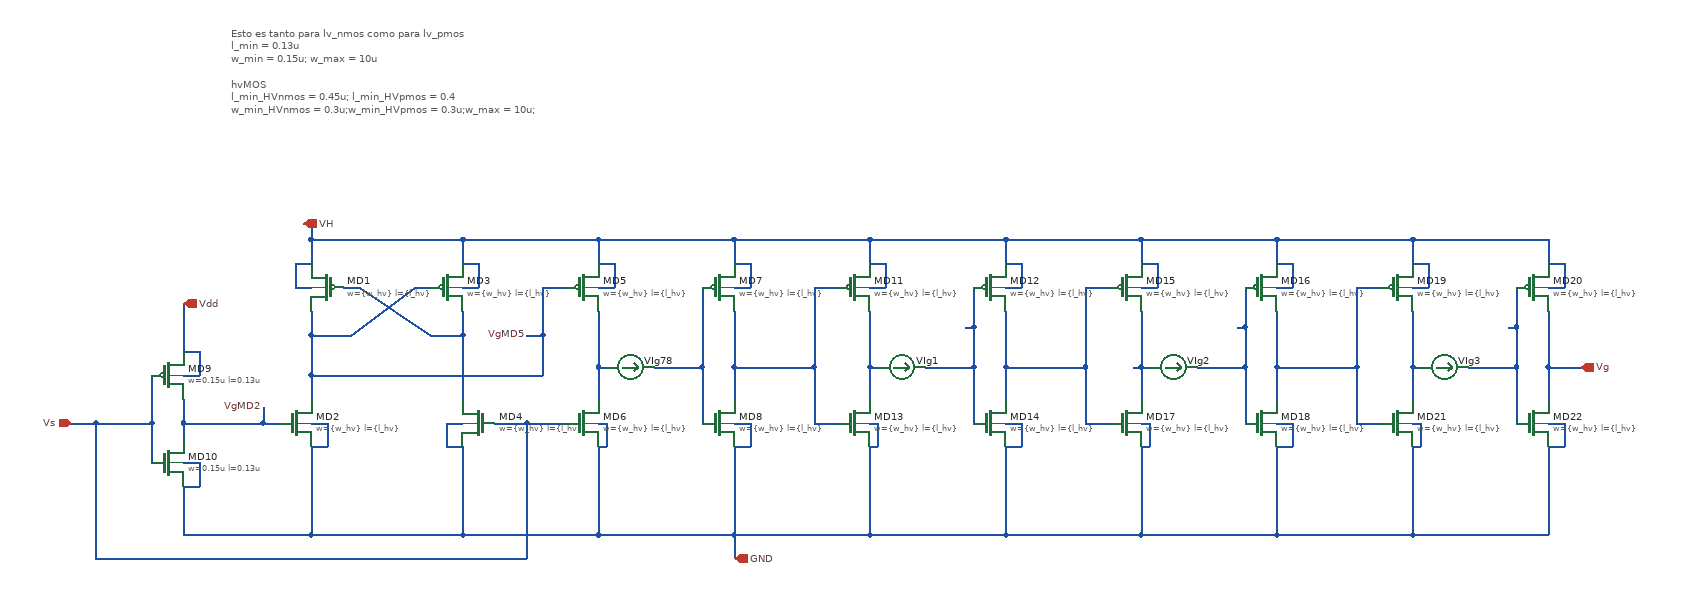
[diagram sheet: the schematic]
v {xschem version=3.4.5 file_version=1.2
}
G {}
K {}
V {}
S {}
E {}
T {Esto es tanto para lv_nmos como para lv_pmos
l_min = 0.13u
w_min = 0.15u; w_max = 10u

hvMOS
l_min_HVnmos = 0.45u; l_min_HVpmos = 0.4
w_min_HVnmos = 0.3u;w_min_HVpmos = 0.3u;w_max = 10u;
} -30 -500 0 0 0.4 0.4 {}
N -90 80 -90 140 {
lab=GND}
N -90 -0 -90 20 {
lab=VgMD2}
N -90 -30 -90 -0 {
lab=VgMD2}
N 70 -60 70 -30 {
lab=VgMD5}
N 10 0 30 0 {
lab=VgMD2}
N 110 -170 130 -170 {
lab=#net1}
N 430 -70 430 -30 {
lab=#net2}
N 260 -110 260 -30 {
lab=#net1}
N 130 -170 220 -110 {
lab=#net1}
N 220 -110 260 -110 {
lab=#net1}
N 260 -140 260 -110 {
lab=#net1}
N 70 -110 120 -110 {
lab=VgMD5}
N 70 -140 70 -110 {
lab=VgMD5}
N 200 -170 220 -170 {
lab=VgMD5}
N 120 -110 200 -170 {
lab=VgMD5}
N 70 -60 360 -60 {
lab=VgMD5}
N 70 -110 70 -60 {
lab=VgMD5}
N 360 -110 360 -60 {
lab=VgMD5}
N 360 -170 390 -170 {
lab=VgMD5}
N 340 0 390 0 {
lab=Vs}
N 340 0 340 170 {
lab=Vs}
N 300 0 340 0 {
lab=Vs}
N -200 170 340 170 {
lab=Vs}
N -200 -0 -200 170 {
lab=Vs}
N 430 140 600 140 {
lab=GND}
N 600 30 600 140 {
lab=GND}
N 430 30 430 140 {
lab=GND}
N 260 140 430 140 {
lab=GND}
N 260 30 260 140 {
lab=GND}
N 70 140 260 140 {
lab=GND}
N 70 30 70 140 {
lab=GND}
N -90 140 70 140 {
lab=GND}
N -130 0 -130 50 {
lab=Vs}
N -200 0 -130 0 {
lab=Vs}
N -130 -60 -130 0 {
lab=Vs}
N 560 -70 560 0 {
lab=#net3}
N 430 -140 430 -70 {
lab=#net2}
N 600 -70 600 -30 {
lab=#net4}
N 70 -230 70 -200 {
lab=VH}
N 430 -230 600 -230 {
lab=VH}
N 600 -230 600 -200 {
lab=VH}
N 430 -230 430 -200 {
lab=VH}
N 260 -230 430 -230 {
lab=VH}
N 260 -230 260 -200 {
lab=VH}
N 70 -230 260 -230 {
lab=VH}
N 70 -250 70 -230 {
lab=VH}
N 60 -250 70 -250 {
lab=VH}
N -90 -150 -90 -90 {
lab=Vdd}
N -230 0 -200 -0 {
lab=Vs}
N 600 140 600 170 {
lab=GND}
N 600 -70 700 -70 {
lab=#net4}
N 600 -140 600 -70 {
lab=#net4}
N 70 0 90 0 {
lab=GND}
N 90 0 90 30 {
lab=GND}
N 70 30 90 30 {
lab=GND}
N 240 0 260 0 {
lab=GND}
N 240 0 240 30 {
lab=GND}
N 240 30 260 30 {
lab=GND}
N 430 0 440 0 {
lab=GND}
N 440 0 440 30 {
lab=GND}
N 430 30 440 30 {
lab=GND}
N 600 0 620 0 {
lab=GND}
N 620 0 620 30 {
lab=GND}
N 600 30 620 30 {
lab=GND}
N 50 -170 70 -170 {
lab=VH}
N 50 -200 50 -170 {
lab=VH}
N 50 -200 70 -200 {
lab=VH}
N 260 -170 280 -170 {
lab=VH}
N 280 -200 280 -170 {
lab=VH}
N 260 -200 280 -200 {
lab=VH}
N 430 -170 450 -170 {
lab=VH}
N 450 -200 450 -170 {
lab=VH}
N 430 -200 450 -200 {
lab=VH}
N 600 -170 620 -170 {
lab=VH}
N 620 -200 620 -170 {
lab=VH}
N 600 -200 620 -200 {
lab=VH}
N -90 -60 -70 -60 {
lab=Vdd}
N -70 -90 -70 -60 {
lab=Vdd}
N -90 -90 -70 -90 {
lab=Vdd}
N -90 50 -70 50 {
lab=GND}
N -70 50 -70 80 {
lab=GND}
N -90 80 -70 80 {
lab=GND}
N 10 -20 10 0 {
lab=VgMD2}
N -90 0 10 0 {
lab=VgMD2}
N 340 -110 360 -110 {
lab=VgMD5}
N 360 -170 360 -110 {
lab=VgMD5}
N 500 -70 560 -70 {
lab=#net3}
N 430 -70 440 -70 {
lab=#net2}
N 560 -170 560 -70 {
lab=#net3}
N 770 -70 770 -30 {
lab=#net5}
N 700 -170 730 -170 {
lab=#net4}
N 700 -0 730 0 {
lab=#net4}
N 770 140 940 140 {
lab=GND}
N 940 30 940 140 {
lab=GND}
N 770 30 770 140 {
lab=GND}
N 600 140 770 140 {
lab=GND}
N 900 -70 900 0 {
lab=#net6}
N 770 -140 770 -70 {
lab=#net5}
N 900 -120 900 -70 {
lab=#net6}
N 940 -70 940 -30 {
lab=#net7}
N 770 -230 940 -230 {
lab=VH}
N 940 -230 940 -200 {
lab=VH}
N 770 -230 770 -200 {
lab=VH}
N 600 -230 770 -230 {
lab=VH}
N 940 -70 1040 -70 {
lab=#net7}
N 940 -140 940 -70 {
lab=#net7}
N 770 0 780 0 {
lab=GND}
N 780 0 780 30 {
lab=GND}
N 770 30 780 30 {
lab=GND}
N 940 0 960 0 {
lab=GND}
N 960 0 960 30 {
lab=GND}
N 940 30 960 30 {
lab=GND}
N 770 -170 790 -170 {
lab=VH}
N 790 -200 790 -170 {
lab=VH}
N 770 -200 790 -200 {
lab=VH}
N 940 -170 960 -170 {
lab=VH}
N 960 -200 960 -170 {
lab=VH}
N 940 -200 960 -200 {
lab=VH}
N 840 -70 900 -70 {
lab=#net6}
N 770 -70 780 -70 {
lab=#net5}
N 890 -120 900 -120 {
lab=#net6}
N 900 -170 900 -120 {
lab=#net6}
N 1110 -70 1110 -30 {
lab=#net8}
N 1040 -170 1070 -170 {
lab=#net7}
N 1040 -0 1070 0 {
lab=#net7}
N 1110 140 1280 140 {
lab=GND}
N 1280 30 1280 140 {
lab=GND}
N 1110 30 1110 140 {
lab=GND}
N 940 140 1110 140 {
lab=GND}
N 1240 -70 1240 0 {
lab=#net9}
N 1110 -140 1110 -70 {
lab=#net8}
N 1240 -120 1240 -70 {
lab=#net9}
N 1280 -70 1280 -30 {
lab=#net10}
N 1110 -230 1280 -230 {
lab=VH}
N 1280 -230 1280 -200 {
lab=VH}
N 1110 -230 1110 -200 {
lab=VH}
N 940 -230 1110 -230 {
lab=VH}
N 1280 -70 1380 -70 {
lab=#net10}
N 1280 -140 1280 -70 {
lab=#net10}
N 1110 0 1120 0 {
lab=GND}
N 1120 0 1120 30 {
lab=GND}
N 1110 30 1120 30 {
lab=GND}
N 1280 0 1300 0 {
lab=GND}
N 1300 0 1300 30 {
lab=GND}
N 1280 30 1300 30 {
lab=GND}
N 1110 -170 1130 -170 {
lab=VH}
N 1130 -200 1130 -170 {
lab=VH}
N 1110 -200 1130 -200 {
lab=VH}
N 1280 -170 1300 -170 {
lab=VH}
N 1300 -200 1300 -170 {
lab=VH}
N 1280 -200 1300 -200 {
lab=VH}
N 1100 -70 1110 -70 {
lab=#net8}
N 1180 -70 1240 -70 {
lab=#net9}
N 1110 -70 1120 -70 {
lab=#net8}
N 1230 -120 1240 -120 {
lab=#net9}
N 1240 -170 1240 -120 {
lab=#net9}
N 1450 -70 1450 -30 {
lab=#net11}
N 1380 -170 1410 -170 {
lab=#net10}
N 1380 0 1410 0 {
lab=#net10}
N 1450 140 1620 140 {
lab=GND}
N 1620 30 1620 140 {
lab=GND}
N 1450 30 1450 140 {
lab=GND}
N 1280 140 1450 140 {
lab=GND}
N 1580 -70 1580 0 {
lab=#net12}
N 1450 -140 1450 -70 {
lab=#net11}
N 1580 -120 1580 -70 {
lab=#net12}
N 1620 -70 1620 -30 {
lab=Vg}
N 1450 -230 1620 -230 {
lab=VH}
N 1620 -230 1620 -200 {
lab=VH}
N 1450 -230 1450 -200 {
lab=VH}
N 1280 -230 1450 -230 {
lab=VH}
N 1620 -70 1660 -70 {
lab=Vg}
N 1620 -140 1620 -70 {
lab=Vg}
N 1450 0 1460 0 {
lab=GND}
N 1460 0 1460 30 {
lab=GND}
N 1450 30 1460 30 {
lab=GND}
N 1620 0 1640 0 {
lab=GND}
N 1640 0 1640 30 {
lab=GND}
N 1620 30 1640 30 {
lab=GND}
N 1450 -170 1470 -170 {
lab=VH}
N 1470 -200 1470 -170 {
lab=VH}
N 1450 -200 1470 -200 {
lab=VH}
N 1620 -170 1640 -170 {
lab=VH}
N 1640 -200 1640 -170 {
lab=VH}
N 1620 -200 1640 -200 {
lab=VH}
N 1520 -70 1580 -70 {
lab=#net12}
N 1450 -70 1460 -70 {
lab=#net11}
N 1570 -120 1580 -120 {
lab=#net12}
N 1580 -170 1580 -120 {
lab=#net12}
N 700 -70 700 -0 {
lab=#net4}
N 700 -170 700 -70 {
lab=#net4}
N 1040 -70 1040 -0 {
lab=#net7}
N 1040 -170 1040 -70 {
lab=#net7}
N 1380 -70 1380 0 {
lab=#net10}
N 1380 -170 1380 -70 {
lab=#net10}
C {sg13g2_pr/sg13_lv_pmos.sym} -110 -60 0 0 {name=MD9
l=0.13u
w=0.15u
ng=1
m=3
model=sg13_lv_pmos
spiceprefix=X
}
C {sg13g2_pr/sg13_lv_nmos.sym} -110 50 2 1 {name=MD10
l = 0.13u
w = 0.15u
ng= 1
m= 1
model=sg13_lv_nmos
spiceprefix=X
}
C {sg13g2_pr/sg13_hv_pmos.sym} 90 -170 0 1 {name=MD1
l=\{l_hv\}
w=\{w_hv\}
ng= 1
m= 1
model=sg13_hv_pmos
spiceprefix=X
}
C {sg13g2_pr/sg13_hv_nmos.sym} 50 0 2 1 {name=MD2
l = \{l_hv\}
w = \{w_hv\}
ng= 1
m= 3
model=sg13_hv_nmos
spiceprefix=X
}
C {sg13g2_pr/sg13_hv_nmos.sym} 410 0 2 1 {name=MD6
l=\{l_hv\}
w=\{w_hv\}
ng= 1
m=\{mult1_GD1\}
model=sg13_hv_nmos
spiceprefix=X
}
C {iopin.sym} 60 -250 0 1 {name=p1 lab=VH}
C {iopin.sym} -90 -150 0 1 {name=p2 lab=Vdd}
C {ipin.sym} -230 0 0 0 {name=p3 lab=Vs}
C {iopin.sym} 600 170 0 1 {name=p5 lab=GND}
C {lab_pin.sym} 10 -20 0 0 {name=p6 sig_type=std_logic lab=VgMD2}
C {lab_pin.sym} 340 -110 0 0 {name=p7 sig_type=std_logic lab=VgMD5}
C {ammeter.sym} 470 -70 3 0 {name=VIg78 savecurrent=true spice_ignore=0}
C {ammeter.sym} 810 -70 3 0 {name=VIg1 savecurrent=true spice_ignore=0}
C {ammeter.sym} 1150 -70 3 0 {name=VIg2 savecurrent=true spice_ignore=0}
C {opin.sym} 1660 -70 0 0 {name=p13 lab=Vg}
C {ammeter.sym} 1490 -70 3 0 {name=VIg3 savecurrent=true spice_ignore=0}
C {sg13g2_pr/sg13_hv_pmos.sym} 240 -170 0 0 {name=MD3
l=\{l_hv\}
w=\{w_hv\}
ng= 1
m= 1
model=sg13_hv_pmos
spiceprefix=X
}
C {sg13g2_pr/sg13_hv_nmos.sym} 280 0 2 0 {name=MD4
l = \{l_hv\}
w = \{w_hv\}
ng= 1
m= 3
model=sg13_hv_nmos
spiceprefix=X
}
C {sg13g2_pr/sg13_hv_pmos.sym} 410 -170 0 0 {name=MD5
l=\{l_hv\}
w=\{w_hv\}
ng= 1
m= \{3*mult1_GD1\}
model=sg13_hv_pmos
spiceprefix=X
}
C {sg13g2_pr/sg13_hv_pmos.sym} 580 -170 0 0 {name=MD7
l=\{l_hv\}
w=\{w_hv\}
ng= 1
m= \{3*mult2_GD1\}
model=sg13_hv_pmos
spiceprefix=X
}
C {sg13g2_pr/sg13_hv_pmos.sym} 750 -170 0 0 {name=MD11
l=\{l_hv\}
w=\{w_hv\}
ng= 1
m= \{3*mult3_GD1\}
model=sg13_hv_pmos
spiceprefix=X
}
C {sg13g2_pr/sg13_hv_pmos.sym} 920 -170 0 0 {name=MD12
l=\{l_hv\}
w=\{w_hv\}
ng= 1
m= \{3*mult4_GD1\}
model=sg13_hv_pmos
spiceprefix=X
}
C {sg13g2_pr/sg13_hv_pmos.sym} 1090 -170 0 0 {name=MD15
l=\{l_hv\}
w=\{w_hv\}
ng= 1
m= \{3*mult5_GD1\}
model=sg13_hv_pmos
spiceprefix=X
}
C {sg13g2_pr/sg13_hv_pmos.sym} 1260 -170 0 0 {name=MD16
l=\{l_hv\}
w=\{w_hv\}
ng= 1
m= \{3*mult6_GD1\}
model=sg13_hv_pmos
spiceprefix=X
}
C {sg13g2_pr/sg13_hv_pmos.sym} 1430 -170 0 0 {name=MD19
l=\{l_hv\}
w=\{w_hv\}
ng= 1
m= \{3*mult7_GD1\}
model=sg13_hv_pmos
spiceprefix=X
}
C {sg13g2_pr/sg13_hv_pmos.sym} 1600 -170 0 0 {name=MD20
l=\{l_hv\}
w=\{w_hv\}
ng= 1
m= \{3*mult8_GD1\}
model=sg13_hv_pmos
spiceprefix=X
}
C {sg13g2_pr/sg13_hv_nmos.sym} 580 0 2 1 {name=MD8
l=\{l_hv\}
w=\{w_hv\}
ng= 1
m=\{mult2_GD1\}
model=sg13_hv_nmos
spiceprefix=X
}
C {sg13g2_pr/sg13_hv_nmos.sym} 750 0 2 1 {name=MD13
l=\{l_hv\}
w=\{w_hv\}
ng= 1
m=\{mult3_GD1\}
model=sg13_hv_nmos
spiceprefix=X
}
C {sg13g2_pr/sg13_hv_nmos.sym} 920 0 2 1 {name=MD14
l=\{l_hv\}
w=\{w_hv\}
ng= 1
m=\{mult4_GD1\}
model=sg13_hv_nmos
spiceprefix=X
}
C {sg13g2_pr/sg13_hv_nmos.sym} 1090 0 2 1 {name=MD17
l=\{l_hv\}
w=\{w_hv\}
ng= 1
m=\{mult5_GD1\}
model=sg13_hv_nmos
spiceprefix=X
}
C {sg13g2_pr/sg13_hv_nmos.sym} 1260 0 2 1 {name=MD18
l=\{l_hv\}
w=\{w_hv\}
ng= 1
m=\{mult6_GD1\}
model=sg13_hv_nmos
spiceprefix=X
}
C {sg13g2_pr/sg13_hv_nmos.sym} 1430 0 2 1 {name=MD21
l=\{l_hv\}
w=\{w_hv\}
ng= 1
m=\{mult7_GD1\}
model=sg13_hv_nmos
spiceprefix=X
}
C {sg13g2_pr/sg13_hv_nmos.sym} 1600 0 2 1 {name=MD22
l=\{l_hv\}
w=\{w_hv\}
ng= 1
m=\{mult8_GD1\}
model=sg13_hv_nmos
spiceprefix=X
}
